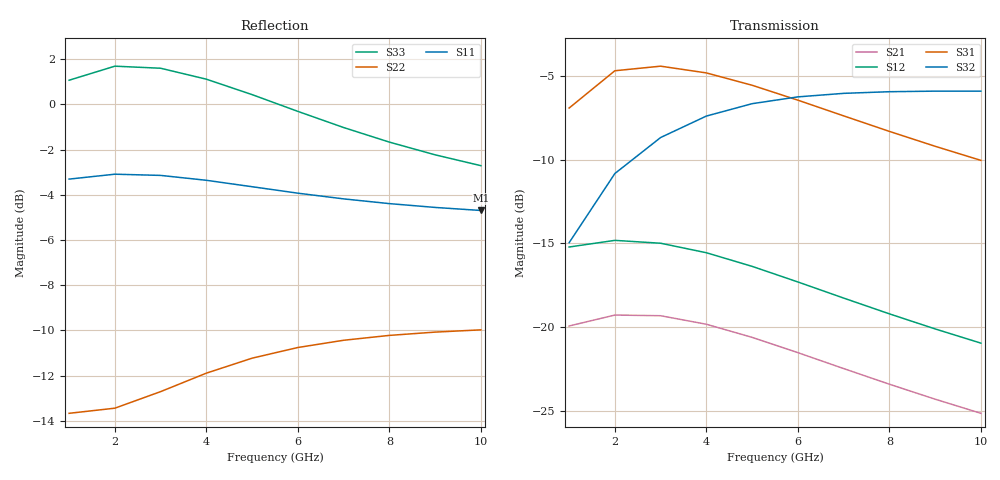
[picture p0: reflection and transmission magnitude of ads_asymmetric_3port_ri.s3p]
! Created Fri Aug 21 13:03:17 2026
# ghz S ri R 50
! 3 Port Network Data from SP1.SP block
! freq  reS11  imS11  reS12  imS12  reS13  imS13
!  reS21  imS21
!  reS22  imS22  reS23  imS23
!  reS31  imS31  reS32  imS32
!  reS33  imS33
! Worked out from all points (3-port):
!   10 points, 1 GHz to 10 GHz, reference 50 ohm
!   strongest paths, dB at 1 GHz, 3 GHz, 6 GHz, 8 GHz, 10 GHz:
!     S32: -15.0, -8.7, -6.3, -5.9, -5.9
!     S31: -6.9, -4.4, -6.5, -8.3, -10.0
!     S12: -15.2, -15.0, -17.3, -19.2, -21.0
!     S21: -19.9, -19.3, -21.5, -23.4, -25.2
!   lowest |S11| = -4.7 dB at 10 GHz (marker M1), VSWR 3.79, Z = 13.2 - j2.87 ohm
!   |S11| at or under -10 dB: nowhere
1  -0.6821 0.0463  -0.171 0.0284  -0.0908 -0.0989
   -0.1 -0.012  0.2069 -0.0127  -0.0108 -0.0708
   -0.4133 -0.1797  -0.1456 -0.1032  -0.0304 -1.131
2  -0.701 0.000403  -0.1809 -0.0136  -0.1169 -0.1235
   -0.1025 -0.0357  0.209 -0.0398  -0.0198 -0.0973
   -0.5576 -0.1683  -0.196 -0.2101  -0.6223 -1.044
3  -0.6957 -0.0364  -0.17 -0.0523  -0.1058 -0.1388
   -0.0924 -0.0559  0.223 -0.0619  -0.00997 -0.1081
   -0.5596 -0.2196  -0.1727 -0.325  -0.7588 -0.9333
4  -0.6766 -0.0631  -0.1463 -0.0797  -0.0816 -0.1447
   -0.0756 -0.0683  0.2431 -0.0747  0.00599 -0.1091
   -0.504 -0.2744  -0.1035 -0.4138  -0.7519 -0.8536
5  -0.653 -0.078  -0.1191 -0.094  -0.057 -0.1413
   -0.058 -0.0728  0.263 -0.0787  0.0206 -0.1034
   -0.4287 -0.3068  -0.0186 -0.4641  -0.7055 -0.7797
6  -0.6308 -0.0836  -0.0943 -0.0984  -0.0369 -0.1324
   -0.043 -0.0719  0.2794 -0.0769  0.0314 -0.0947
   -0.3554 -0.3164  0.061 -0.4829  -0.6571 -0.7073
7  -0.6125 -0.0835  -0.0742 -0.0968  -0.0221 -0.1213
   -0.0314 -0.0682  0.2919 -0.0722  0.0385 -0.0855
   -0.2929 -0.3109  0.1274 -0.4821  -0.6177 -0.6396
8  -0.598 -0.0805  -0.0586 -0.0924  -0.0118 -0.1101
   -0.0228 -0.0635  0.301 -0.0665  0.0429 -0.0769
   -0.2426 -0.2975  0.1799 -0.4711  -0.5885 -0.5789
9  -0.5868 -0.0762  -0.0467 -0.0869  -0.0046 -0.0998
   -0.0166 -0.0586  0.3075 -0.0608  0.0454 -0.0693
   -0.203 -0.2808  0.2206 -0.4557  -0.5676 -0.5258
10  -0.5782 -0.0715  -0.0377 -0.0812  0.0003 -0.0906
    -0.012 -0.0539  0.3122 -0.0555  0.0467 -0.0628
    -0.1719 -0.2634  0.2521 -0.4389  -0.5527 -0.4801
